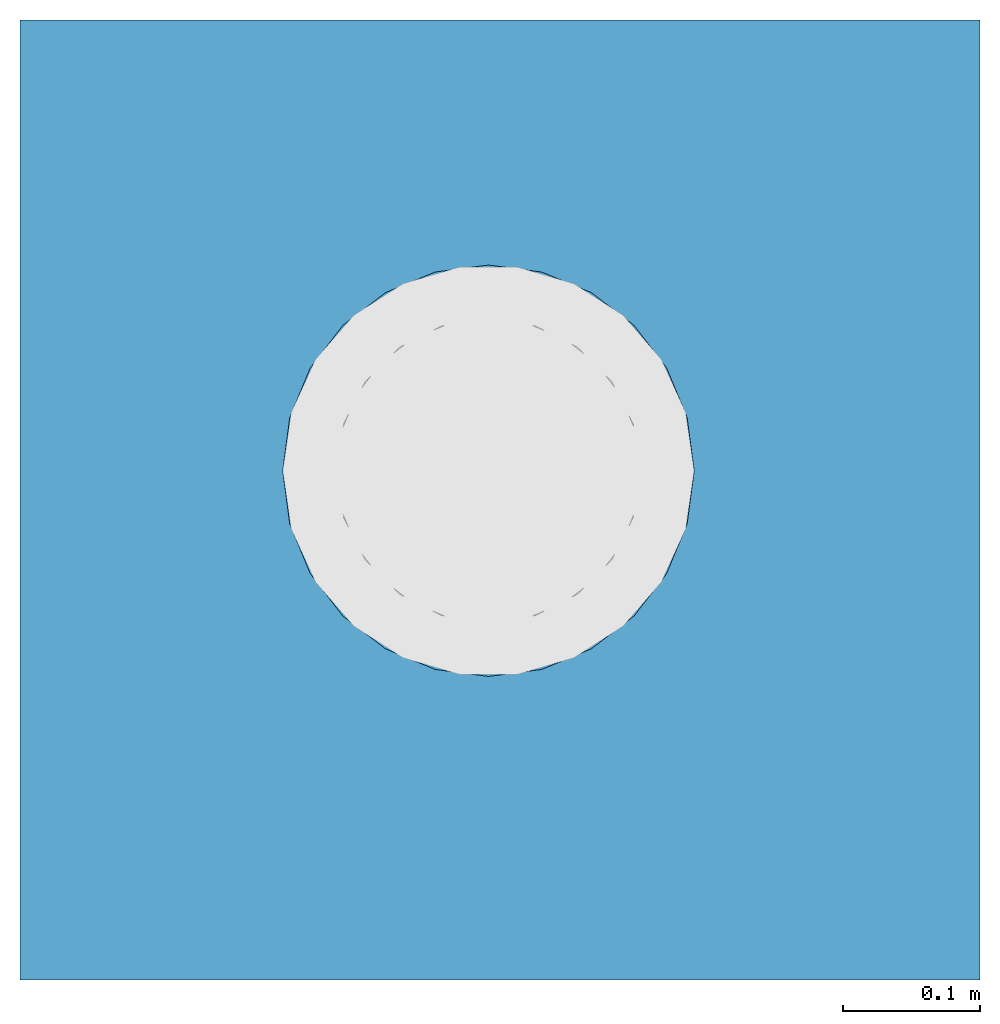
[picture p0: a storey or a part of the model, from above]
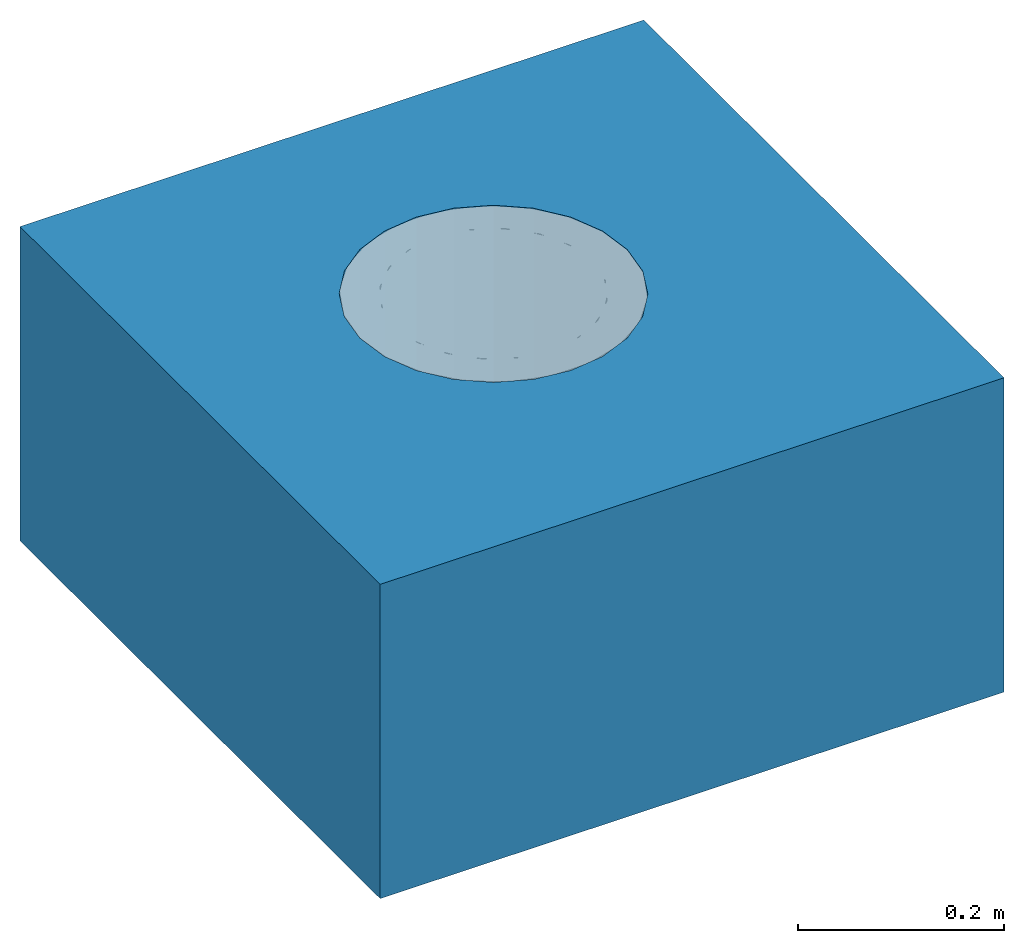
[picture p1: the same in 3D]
Properties of the parts of a building model (IFC2X3)

# File
Description: ViewDefinition [CoordinationView]
File name: Project Number
Time: 2014-10-13T17:54:33
Written by: The EXPRESS Data Manager Version 5.01.0100.02.64mod : 6 Jun 2012
Made in: 20130308_1515(x64) - Exporter 2014.0.2013.0308 - Default UI
Comment: STEP Physical File produced by: The EXPRESS Data Manager Version 5.01.0100.02.64mod : 6 Jun 2012 * Module: EDMstepFileFactory/EDMstandAlone * Creation date: Mon Oct 13 17:54:33 2014 * Host: IN-BLR-PC-0012 * Database: C:\Users\pponnur\AppData\Local\Temp\{4CC04798-C517-4EC6-9E51-1223285CA913}\ifc * Database version: 5507 * Database creation date: Mon Oct 13 17:54:32 2014 * Schema: IFC2X3 * Model: DataRepository.ifc * Model creation date: Mon Oct 13 17:54:32 2014 * Header model: DataRepository.ifc_HeaderModel * Header model creation date: Mon Oct 13 17:54:32 2014 * EDMuser: sdai-user * EDMgroup: sdai-group * License ID and type: 5605 : Permanent license. Expiry date: * EDMstepFileFactory options: 020000

# IfcProject, Project Number
LongName: Project Name; Phase: Project Status

# IfcSite, Default
RefLatitude: 42, 21, 30, 344238; RefLongitude: -71, -3, -35, -194702; RefElevation: 0 mm

# IfcBuilding
Pset_BuildingCommon - NumberOfStoreys: 1
Other - Project Issue Date: Issue Date; Project Number: Project Number; Project Name: Project Name; Client Name: Owner; Project Address: Enter address here; Project Status: Project Status

# IfcBuildingStorey, Level 1
LongName: Level 1; Elevation: 0 mm
Constraints - Elevation Base: Project Base Point; Elevation: 0 mm
Graphics - Symbol at End 1 Default: no; Line Weight: 1; Symbol at End 2 Default: yes; Symbol: Level Head - Circle: Level Head - Circle; Color: 0; Line Pattern: Grid Line 1/2"
Identity Data - Name: Level 1; Structural: no; Building Story: yes
Dimensions - Computation Height: 0 mm

# IfcFlowTerminal: 408067 Body / 408242 Top - 160mm Dia Outlet, ACO BD Gully 218 Telescopic - Vinyl Top - Vertical Outlet with Location Flange - 222 mm:408067 Body / 408242 Top - 160mm Dia Outlet:201465
In: Level 1
Material: Stainless Steel AISI 304, Rubber, Nitrile
Dimensions - Gully Outlet Depth: 77 mm; Gully Outlet Radius: 80 mm; Gully Outlet Diameter: 160 mm; Floor To Gully Height: 68 mm; Rasing Piece Height: 500 mm; Outlet Void End: -315 mm; Floor Void End: -238 mm; Outlet Void Start: -238 mm; FFL To Gully Top Height: 68 mm
Identity Data - Mark: 7; E-mail Technical: abdtechnical@aco.co.uk; Watermarked By: www.acobd.com; Address: ACO Business Centre, Caxton Road, Bedford, MK41 0LF; Water Marked With: BIM Manager Premium Suite; Water Mark 1: This file is the property of ACO Technologies PLC; Telephone: +44 (0)1462 816666; Fax: +44 (0)1462 851490; Water Mark 2: This file is water marked and users are prohibited to reproduce, adapt, distribute this information; E-mail Sales: abdcommercial@aco.co.uk; Website: www.acobd.com; Manufacturer: ACO Building Drainage
Construction - 97153 - 222mm Ø - Perforated Grating - Plain - Stainless steel 304: no; 408220 - Foul Air Trap & 408221 - Foul Air Trap Support Ring: yes; 97148 - 222mm Ø - Ladder Grating - Plain - Stainless steel 304: no; 408222 - Silt Basket: yes; 97156 - 222mm Ø - Slot Grating - Plain - Stainless steel 304: no
Other - Raising Piece Detail: no; 408209 - Raising Piece with Location Flange: no; 160 mm Outlet: yes; 110 mm Outlet: no
Mechanical - System Classification: Sanitary
Phasing - Phase Created: New Construction
Model Properties - Raising Piece Product Code 408209: NA; Grating Product Code 97148: Load Class M125 (EN 1253) - Ladder Grating - Plain - Stainless steel 1.4301 (EN 10088) - 222mm Ø; Grating Product Code 97156: Load Class M125 (EN 1253) - Slot Grating - Plain - Stainless steel 1.4301 (EN 10088) - 222mm Ø; Product Code 408221: Foul Air Trap Support Ring - Nitrile; Grating Product Code 97153: Load Class L15 (EN 1253) - Perforated Grating - Plain - Stainless steel 1.4301 (EN 10088) - 222mm Ø; Product Code 408220: Foul Air Trap - Stainless Steel 304; Product Code 408222: Silt Basket - Stainless Steel 304; Product Code 408225: Friction Ring Installation Set - Nitrile
Constraints - Level: Level: Level 1
Pset_ManufacturerTypeInformation - Manufacturer: ACO Building Drainage
General - Price: POA - contact ACO; Gully Material: Stainless Steel Grade 304 (EN 1253); Gully Recycled Material Content: 20 - 30 %; Flow Rate (l/s): 5.0 - 6.3 l/s; Foul Air Trap Seal Recycled Material Content: 0%; Gully Top Size (mm): 242mm Diameter; Foul Air Trap Seal Recyclable: Fully recyclable; Gully Colour: passivated stainless steel surface ( matt grey); Gully Top Product Description: ACO Gully 218 Telescopic Top for Vinyl Floor; Gully Product Description: ACO Gully 218 Telescopic Flange Type DN160 Vertical with Foul Air Trap; Load Class: A15 - C250 (EN 1253); Gully Top Product Code: 408242; Gully Product Code: 408067; Installation guidelines: http://issuu.com/acobuildingdrainage/docs/120820112708-138bdc871b784edfa2b6b8197acfd881?e=0; Gully Recyclable: Fully recyclable; Product Type: Point drainage; Gully top Grate size (mm): 222; Product Standard: EN 1253; Outlet Diameter (mm): 160; Maintenance guidelines: http://issuu.com/acobuildingdrainage/docs/120820112708-138bdc871b784edfa2b6b8197acfd881?e=0; Product Range: ACO Gully 218; NBS Specification: R11 ABOVE GROUND FOUL DRAINAGE SYSTEMS : Clause 315; Foul Air Trap Seal Colour: Black; Gully Flange Type: Location; Foul Air Trap Seal Material: NBR

# IfcOpeningElement: Recess
In: Level 1
Dimensions - Area: 5.27432 ft2; Perimeter: 2800 mm; Thickness: 372.8 mm; Volume: 5.80224 ft3
Phasing - Phase Created: New Construction
Constraints - Room Bounding: yes; Height Offset From Level: 0 mm; Level: Level: Level 1; Related to Mass: no
Structural - Enable Analytical Model: no; Structural: no
Identity Data - Assembly Description: Floor Construction; Assembly Code: B1010
Graphics - Coarse Scale Fill Color: 0
Analytical Properties - Heat Transfer Coefficient (U): 1.55882; Thermal Resistance (R): 0.641509; Roughness: 3; Absorptance: 0.7; Thermal mass: 53301.1
Construction - Function: Interior; Default Thickness: 372.8 mm

# IfcSlab: Floor:Generic - 12", Floor:Generic - 12":184145
In: Level 1
PredefinedType: FLOOR; Material: Plywood, Sheathing 68 mm, Default Floor 304.8 mm
Dimensions - Area: 5.27432 ft2; Perimeter: 2800 mm; Thickness: 372.8 mm; Volume: 5.80224 ft3
Phasing - Phase Created: New Construction
Constraints - Room Bounding: yes; Height Offset From Level: 0 mm; Level: Level: Level 1; Related to Mass: no
Structural - Enable Analytical Model: no; Structural: no
Pset_SlabCommon - Reference: Generic - 12"; IsExternal: no; LoadBearing: yes; ThermalTransmittance: 1.55882 kg/K/s3
Identity Data - Assembly Description: Floor Construction; Assembly Code: B1010
Graphics - Coarse Scale Fill Color: 0
Analytical Properties - Heat Transfer Coefficient (U): 1.55882; Thermal Resistance (R): 0.641509; Roughness: 3; Absorptance: 0.7; Thermal mass: 53301.1
Construction - Function: Interior; Default Thickness: 372.8 mm
